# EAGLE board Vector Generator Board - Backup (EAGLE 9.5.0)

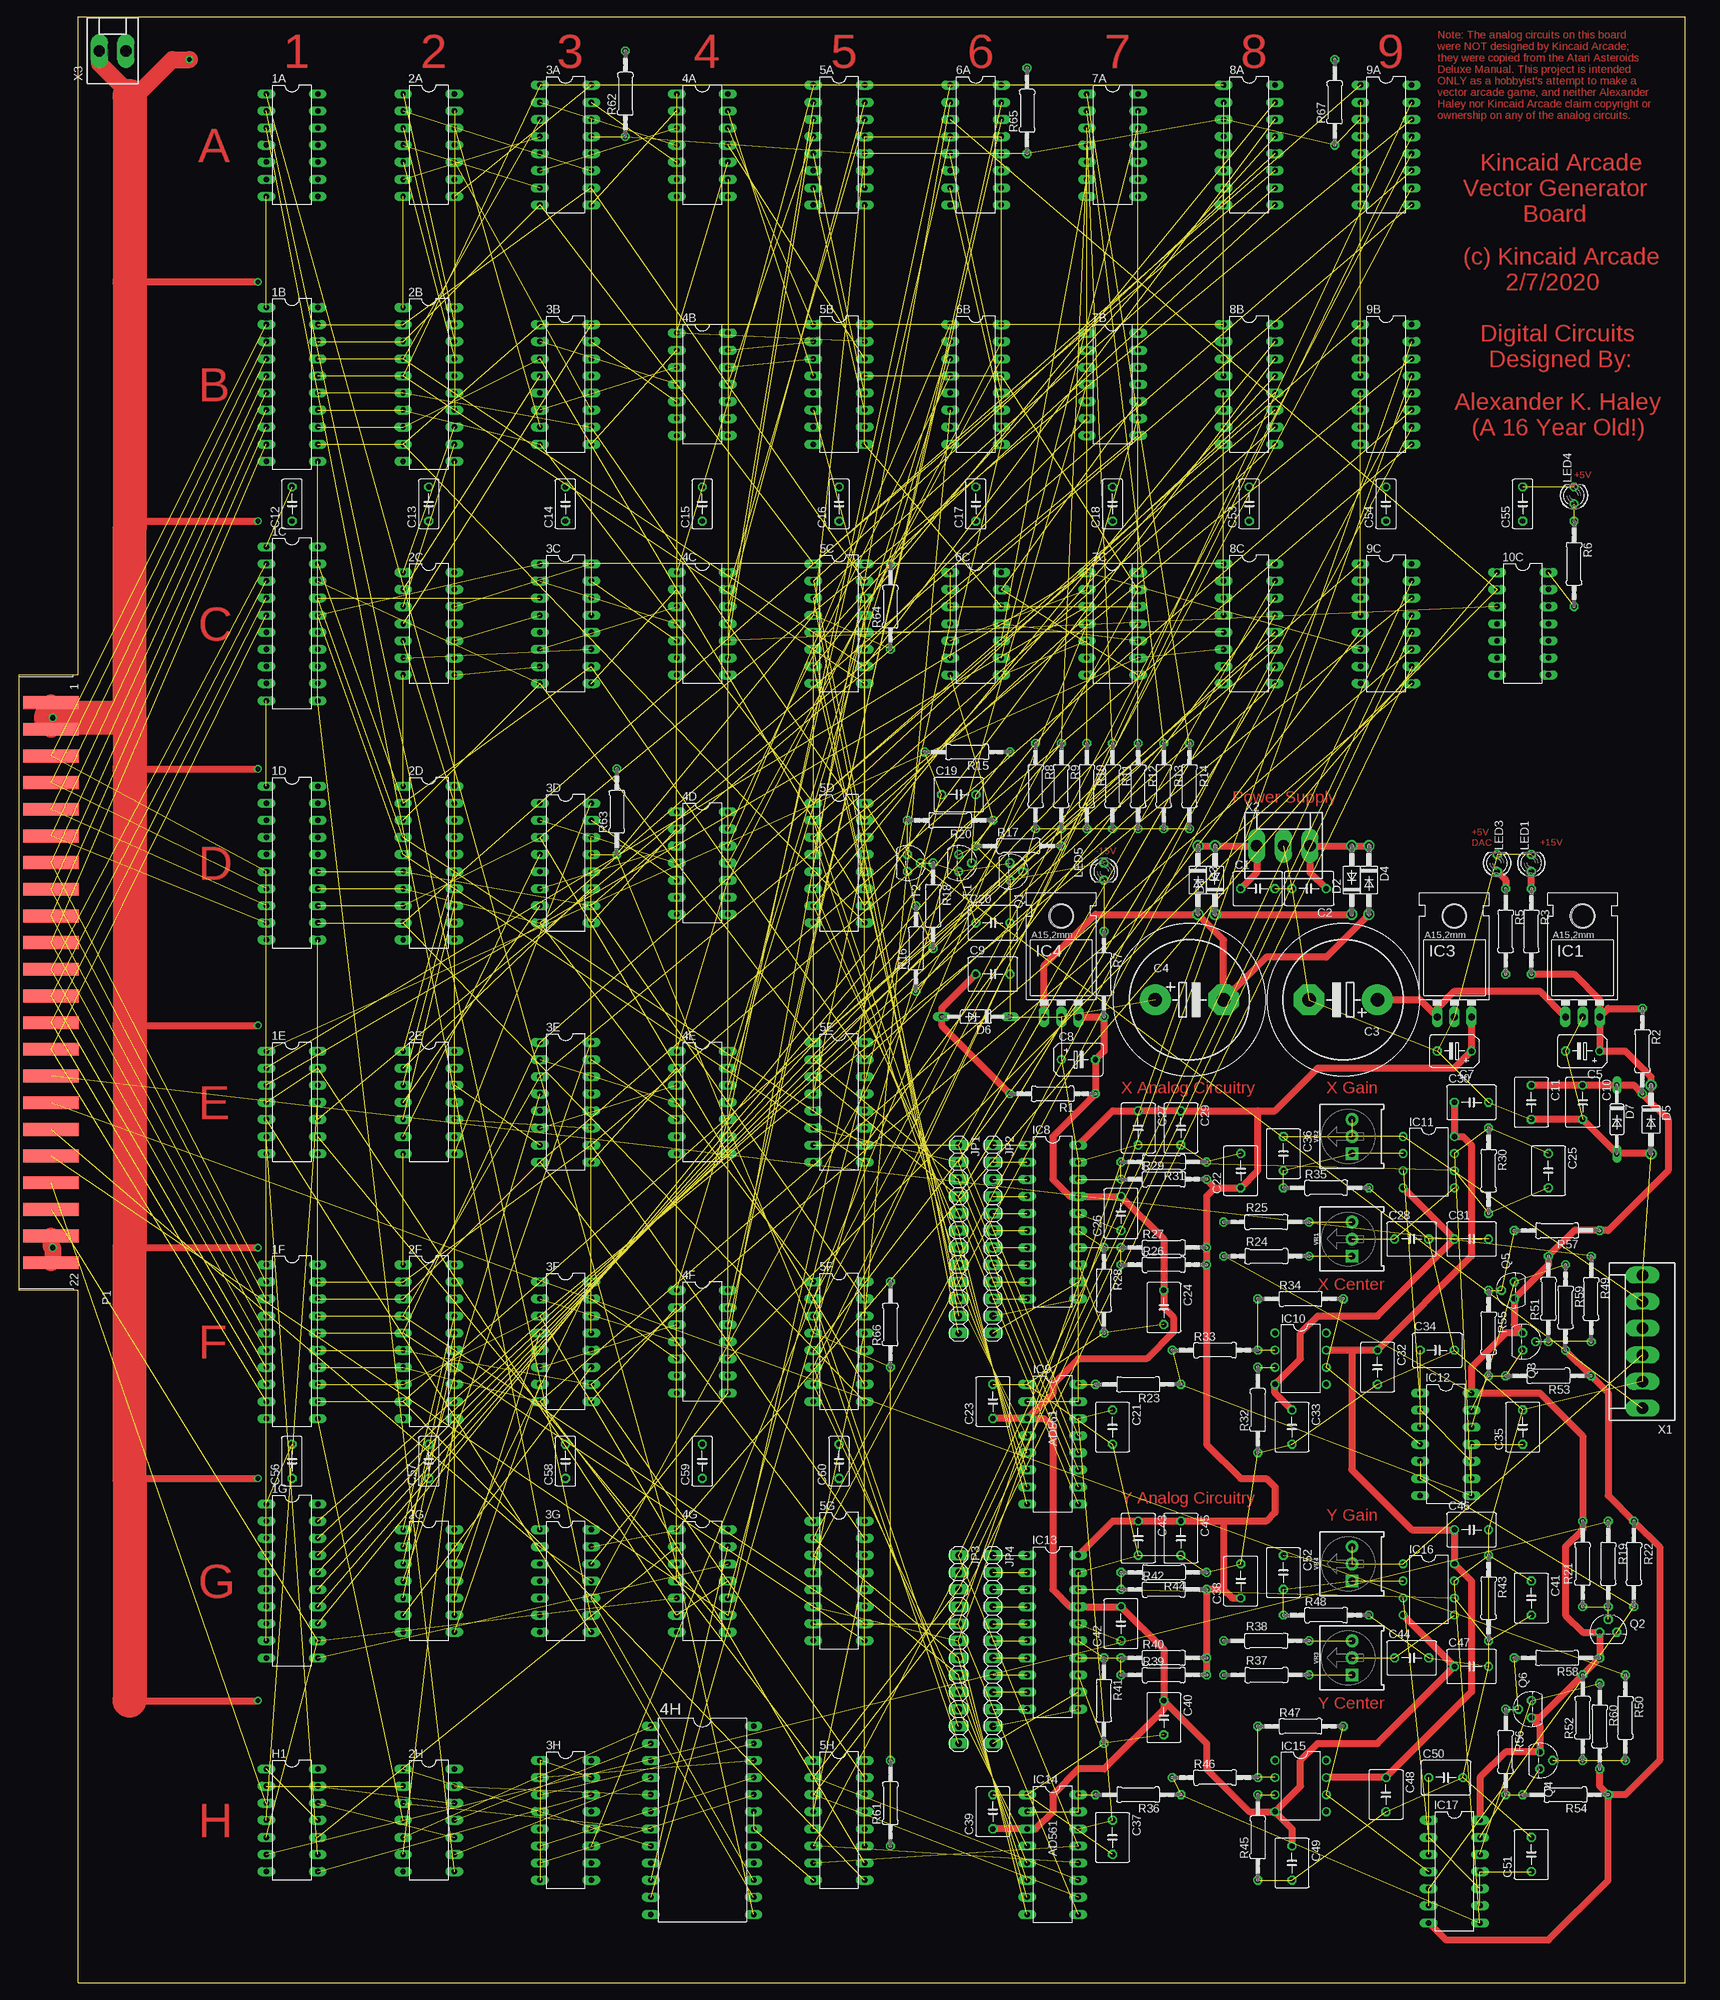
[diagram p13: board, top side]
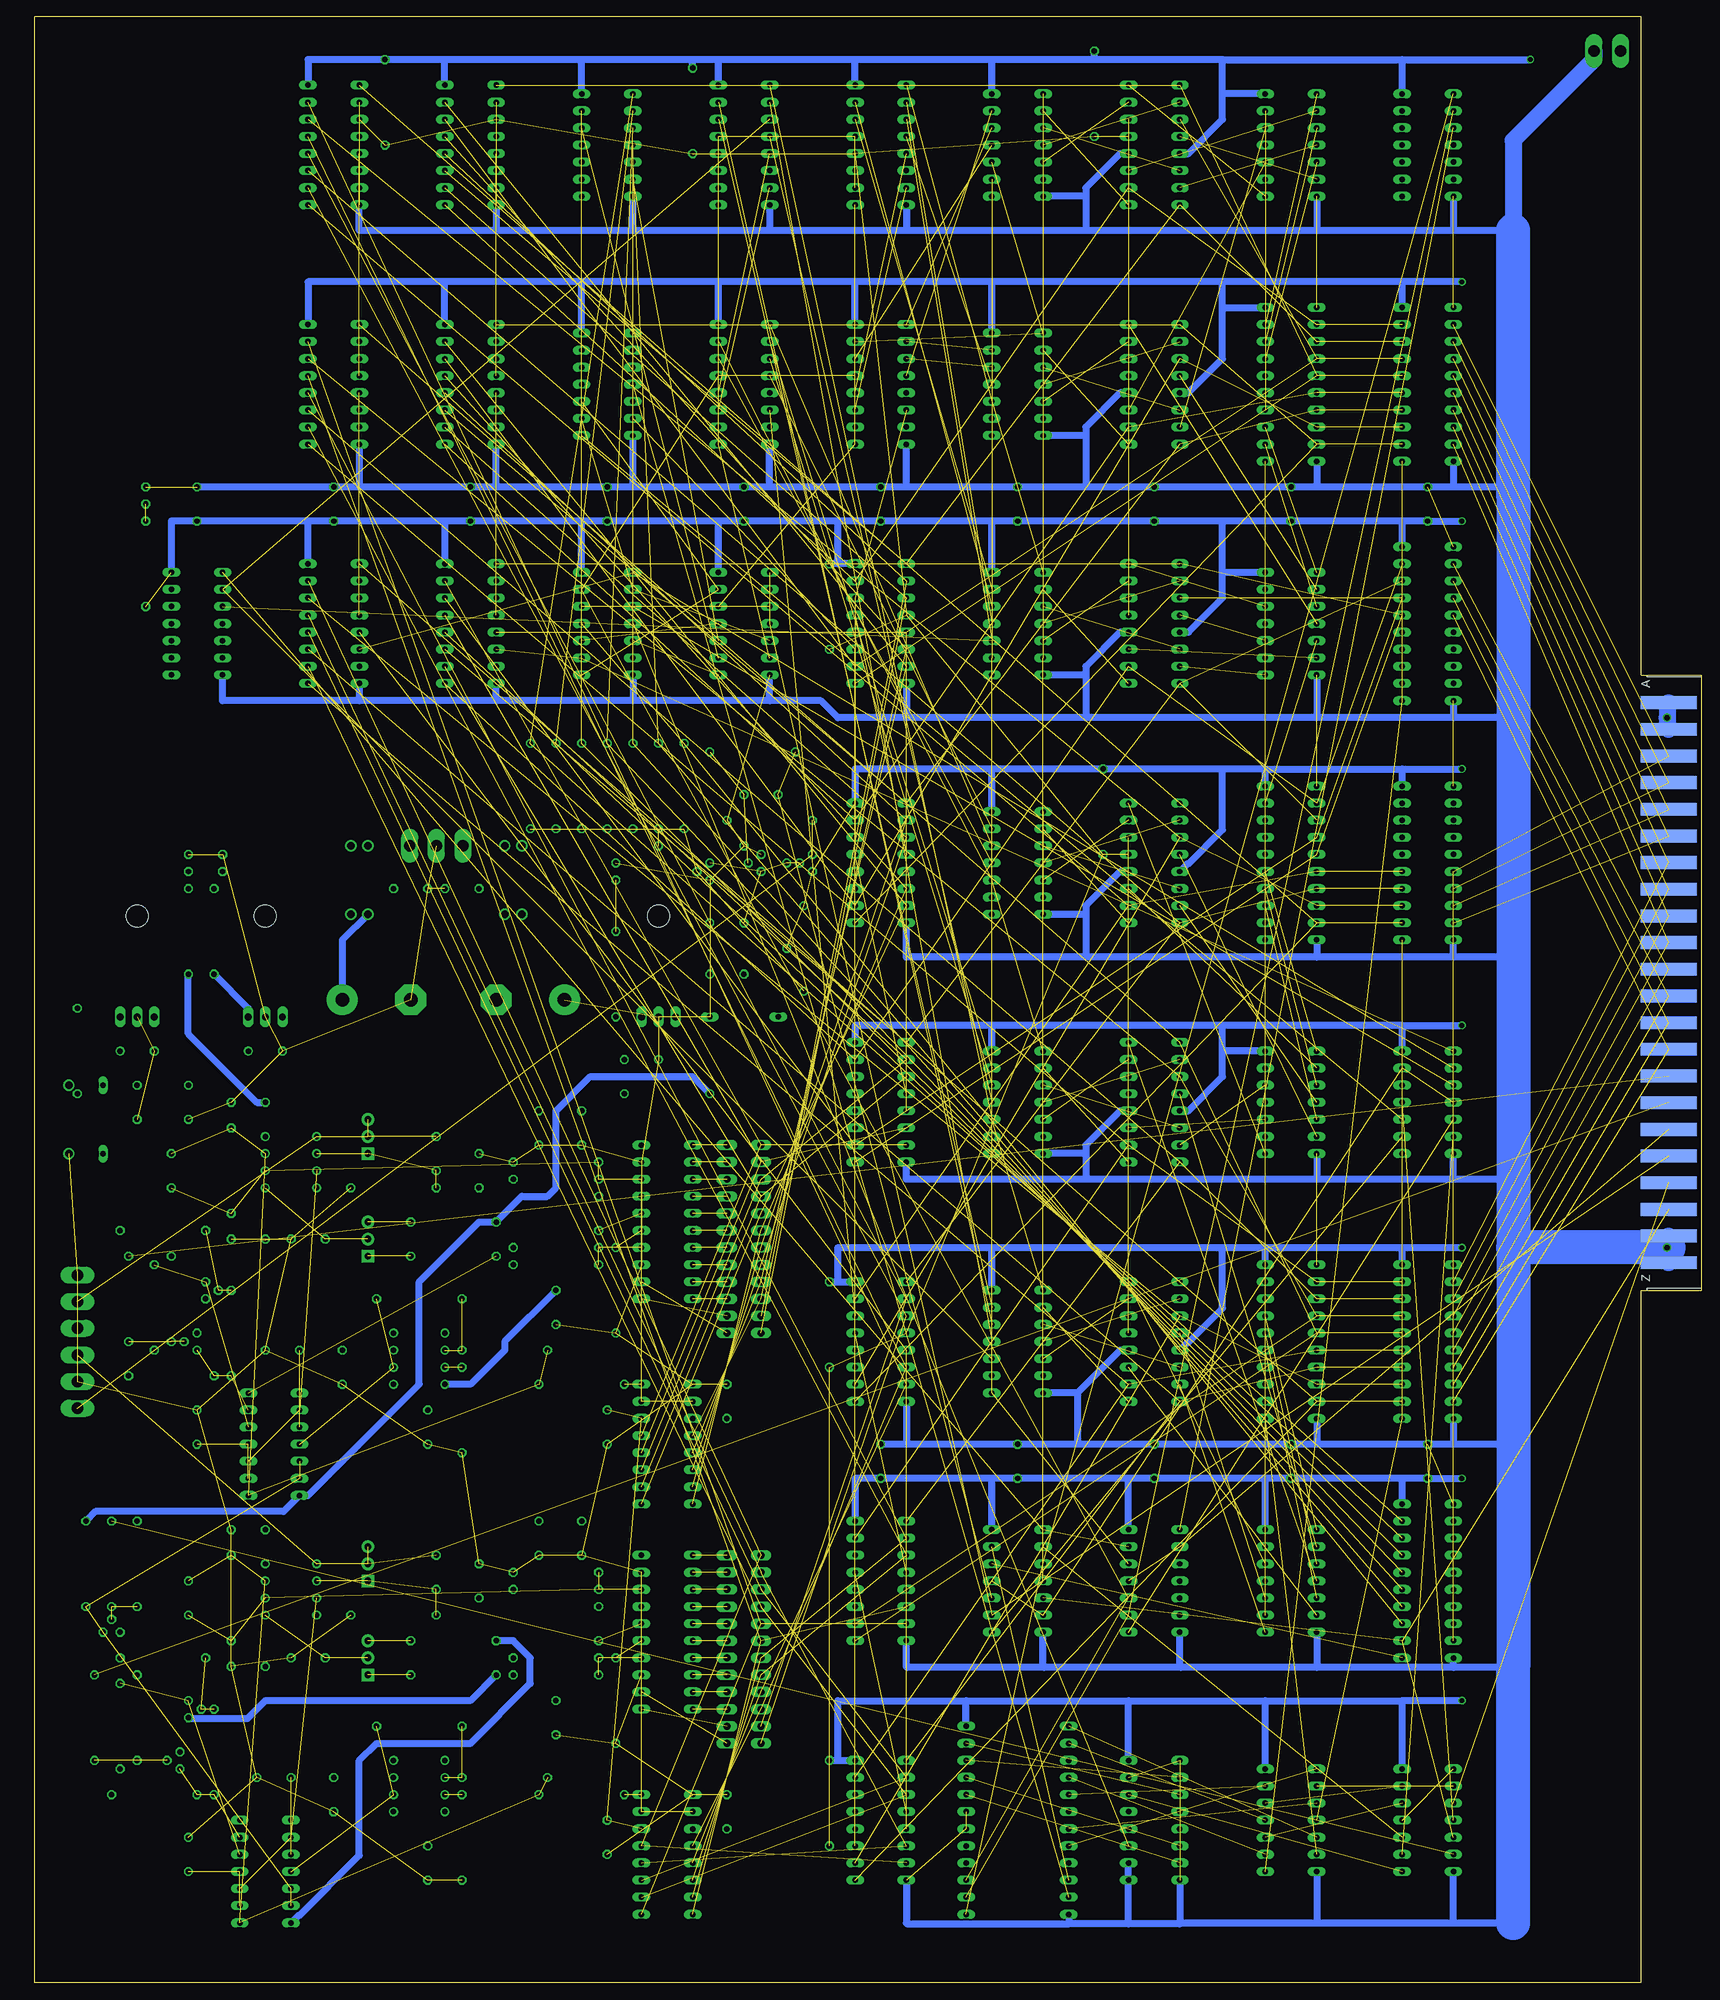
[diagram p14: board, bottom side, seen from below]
Size 247.65 x 292.1 mm. Coordinates in mm from the lower left corner, seen from the top.
Outline: 8.89,0 8.89,102.87 0,102.87 0,194.31 8.89,194.31 8.89,292.1 247.65,292.1 247.65,0 8.89,0
Copper layers (1*16): Top 0.035mm / dielectric 1.5mm / Bottom 0.035mm
Design rules "default": minimum track width 6mil, minimum drill 0.35mm, track to track 6mil, track to pad 6mil, pad to pad 6mil, via to via 6mil, smd to smd 6mil, copper to edge 40mil, drill to drill 6mil, minimum pad ring 10mil, minimum via ring 8mil, stop-mask expansion 4mil, vias tented up to drill 0mil, thermal gap 10mil
Net classes: 0 default: width 0.381 mm, clearance 0.203 mm

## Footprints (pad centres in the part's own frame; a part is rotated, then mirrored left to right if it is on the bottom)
DIL14 = drill 0.813 long: 1 -7.62,-3.81; 2 -5.08,-3.81; 3 -2.54,-3.81; 4 0,-3.81; 5 2.54,-3.81; 6 5.08,-3.81; 7 7.62,-3.81; 8 7.62,3.81; 9 5.08,3.81; 10 2.54,3.81; 11 0,3.81; 12 -2.54,3.81; 13 -5.08,3.81; 14 -7.62,3.81
DIL20 = drill 0.813 long: 1 -11.43,-3.81; 2 -8.89,-3.81; 3 -6.35,-3.81; 4 -3.81,-3.81; 5 -1.27,-3.81; 6 1.27,-3.81; 7 3.81,-3.81; 8 6.35,-3.81; 9 8.89,-3.81; 10 11.43,-3.81; 11 11.43,3.81; 12 8.89,3.81; 13 6.35,3.81; 14 3.81,3.81; 15 1.27,3.81; 16 -1.27,3.81; 17 -3.81,3.81; 18 -6.35,3.81; 19 -8.89,3.81; 20 -11.43,3.81
DIL16 = drill 0.813 long: 1 -8.89,-3.81; 2 -6.35,-3.81; 3 -3.81,-3.81; 4 -1.27,-3.81; 5 1.27,-3.81; 6 3.81,-3.81; 7 6.35,-3.81; 8 8.89,-3.81; 9 8.89,3.81; 10 6.35,3.81; 11 3.81,3.81; 12 1.27,3.81; 13 -1.27,3.81; 14 -3.81,3.81; 15 -6.35,3.81; 16 -8.89,3.81
DIL24-6 = drill 0.813 long: 1 -13.97,-7.62; 2 -11.43,-7.62; 3 -8.89,-7.62; 4 -6.35,-7.62; 5 -3.81,-7.62; 6 -1.27,-7.62; 7 1.27,-7.62; 8 3.81,-7.62; 9 6.35,-7.62; 10 8.89,-7.62; 11 11.43,-7.62; 12 13.97,-7.62; 13 13.97,7.62; 14 11.43,7.62; 15 8.89,7.62; 16 6.35,7.62; 17 3.81,7.62; 18 1.27,7.62; 19 -1.27,7.62; 20 -3.81,7.62; 21 -6.35,7.62; 22 -8.89,7.62; 23 -11.43,7.62; 24 -13.97,7.62
C050-050X075 = drill 0.813 octagon: 1 -2.54,0; 2 2.54,0
EB22,5D = drill 2.007 pad 4.597: + -5.08,0 | drill 2.007 pad 4.597 octagon: - 5.08,0
B45181B = drill 0.813: + -2.54,0 | drill 0.813 octagon: - 2.54,0
C050-030X075 = drill 0.813 octagon: 1 -2.54,0; 2 2.54,0
DO41-10 = drill 1.118: A 5.08,0; C -5.08,0
DO35Z10 = drill 0.813 long: A 5.08,0; C -5.08,0
78XXL = drill 1.016 long: GND 0,-3.81; IN -2.54,-3.81; OUT 2.54,-3.81 | hole 3.302: 0,11.176
DIL08 = drill 0.813 pad 1.27: 1 -3.81,-3.81; 2 -1.27,-3.81; 3 1.27,-3.81; 4 3.81,-3.81; 5 3.81,3.81; 6 1.27,3.81; 7 -1.27,3.81; 8 -3.81,3.81
1X12 = drill 1.016 long: 1 -13.97,0; 2 -11.43,0; 3 -8.89,0; 4 -6.35,0; 5 -3.81,0; 6 -1.27,0; 7 1.27,0; 8 3.81,0; 9 6.35,0; 10 8.89,0; 11 11.43,0; 12 13.97,0
LED3MM = drill 0.813 octagon: A -1.27,0; K 1.27,0
44PINEDGE = smd 1.905 x 8.255: 1 -41.605,4.826; 2 -37.643,4.826; 3 -33.68,4.826; 4 -29.718,4.826; 5 -25.756,4.826; 6 -21.793,4.826; 7 -17.831,4.826; 8 -13.868,4.826; 9 -9.906,4.826; 10 -5.944,4.826; 11 -1.981,4.826; 12 1.981,4.826; 13 5.944,4.826; 14 9.906,4.826; 15 13.868,4.826; 16 17.831,4.826; 17 21.793,4.826; 18 25.756,4.826; 19 29.718,4.826; 20 33.68,4.826; 21 37.643,4.826; 22 41.605,4.826 | smd 1.905 x 8.255 bottom: A -41.605,4.826; B -37.643,4.826; C -33.68,4.826; D -29.718,4.826; E -25.756,4.826; F -21.793,4.826; H -17.831,4.826; J -13.868,4.826; K -9.906,4.826; L -5.944,4.826; M -1.981,4.826; N 1.981,4.826; P 5.944,4.826; R 9.906,4.826; S 13.868,4.826; T 17.831,4.826; U 21.793,4.826; V 25.756,4.826; W 29.718,4.826; X 33.68,4.826; Y 37.643,4.826; Z 41.605,4.826
TO92 = drill 0.813 octagon: 1 1.27,0; 2 0,1.905; 3 -1.27,0
0207/12 = drill 0.813 octagon: 1 -6.35,0; 2 6.35,0
TRIMPOT-PTH-3386U = drill 1.016 pad 1.88 square: 1 -2.54,-0.015 | drill 1.016 pad 1.88: 2 0,-0.015; 3 2.54,-0.015
KK-156-6 = drill 1.7 pad 2.184 long: 1 -9.9,0; 2 -5.94,0; 3 -1.98,0; 4 1.98,0; 5 5.94,0; 6 9.9,0
KK-156-3 = drill 1.7 pad 2.184 long: 1 -3.96,0; 2 0,0; 3 3.96,0
KK-156-2 = drill 1.7 pad 2.184 long: 1 -1.98,0; 2 1.98,0

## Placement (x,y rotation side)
1A  7400N  [DIL14]  40.64,273.05 270 top
1B  74HC573N  [DIL20]  40.64,237.49 270 top
1C  74HC573N  [DIL20]  40.64,201.93 270 top
1D  74HC573N  [DIL20]  40.64,166.37 270 top
1E  74S08N  [DIL14]  40.64,130.81 270 top
1F  74HC573N  [DIL20]  40.64,95.25 270 top
1G  74HC573N  [DIL20]  40.64,59.69 270 top
2A  7404N  [DIL14]  60.96,273.05 270 top
2B  74HC573N  [DIL20]  60.96,237.49 270 top
2C  7404N  [DIL14]  60.96,201.93 270 top
2D  74HC573N  [DIL20]  60.96,166.37 270 top
2E  7404N  [DIL14]  60.96,130.81 270 top
2F  74HC573N  [DIL20]  60.96,95.25 270 top
2G  7404N  [DIL14]  60.96,59.69 270 top
2H  7404N  [DIL14]  60.96,24.13 270 top
3A  7483N  [DIL16]  81.28,273.05 270 top
3B  7483N  [DIL16]  81.28,237.49 270 top
3C  7483N  [DIL16]  81.28,201.93 270 top
3D  7483N  [DIL16]  81.28,166.37 270 top
3E  7483N  [DIL16]  81.28,130.81 270 top
3F  7483N  [DIL16]  81.28,95.25 270 top
3G  74S11N  [DIL14]  81.28,59.69 270 top
3H  74191N  [DIL16]  81.28,24.13 270 top
4A  7495N  [DIL14]  101.6,273.05 270 top
4B  7495N  [DIL14]  101.6,237.49 270 top
4C  7495N  [DIL14]  101.6,201.93 270 top
4D  7495N  [DIL14]  101.6,166.37 270 top
4E  7495N  [DIL14]  101.6,130.81 270 top
4F  7495N  [DIL14]  101.6,95.25 270 top
4G  7404N  [DIL14]  101.6,59.69 270 top
4H  74154N  [DIL24-6]  101.6,24.13 270 top
5A  7497N  [DIL16]  121.92,273.05 270 top
5B  7497N  [DIL16]  121.92,237.49 270 top
5C  74191N  [DIL16]  121.92,201.93 270 top
5D  74191N  [DIL16]  121.92,166.37 270 top
5E  74191N  [DIL16]  121.92,130.81 270 top
5F  74191N  [DIL16]  121.92,95.25 270 top
5G  74191N  [DIL16]  121.92,59.69 270 top
5H  74191N  [DIL16]  121.92,24.13 270 top
6A  7497N  [DIL16]  142.24,273.05 270 top
6B  7497N  [DIL16]  142.24,237.49 270 top
6C  74S11N  [DIL14]  142.24,201.93 270 top
7A  74LS27N  [DIL14]  162.56,273.05 270 top
7B  7432N  [DIL14]  162.56,237.49 270 top
7C  7404N  [DIL14]  162.56,201.93 270 top
8A  7485N  [DIL16]  182.88,273.05 270 top
8B  7485N  [DIL16]  182.88,237.49 270 top
8C  7485N  [DIL16]  182.88,201.93 270 top
9A  7485N  [DIL16]  203.2,273.05 270 top
9B  7485N  [DIL16]  203.2,237.49 270 top
9C  7485N  [DIL16]  203.2,201.93 270 top
10C  7402N  [DIL14]  223.52,201.93 270 top
C1  .1 uf  [C050-050X075]  184.15,162.56 0 top
C2  .1 uf  [C050-050X075]  191.77,162.56 180 top
C3  470 uf  [EB22,5D]  196.85,146.05 180 top
C4  470 uf  [EB22,5D]  173.99,146.05 0 top
C5  1 uf  [B45181B]  232.41,138.43 180 top
C7  1 uf  [B45181B]  213.36,138.43 180 top
C8  1 uf  [B45181B]  157.48,137.16 0 top
C9  .1 uf  [C050-050X075]  144.78,149.86 0 top
C10  .1 uf  [C050-050X075]  232.41,130.81 270 top
C11  22pf  [C050-050X075]  224.79,130.81 270 top
C12  .1uf  [C050-030X075]  40.64,219.71 90 top
C13  .1uf  [C050-030X075]  60.96,219.71 90 top
C14  .1uf  [C050-030X075]  81.28,219.71 90 top
C15  .1uf  [C050-030X075]  101.6,219.71 90 top
C16  .1uf  [C050-030X075]  121.92,219.71 90 top
C17  .1uf  [C050-030X075]  142.24,219.71 90 top
C18  .1uf  [C050-030X075]  162.56,219.71 90 top
C19  270pf  [C050-050X075]  139.7,176.53 0 top
C20  .01uf  [C050-050X075]  144.78,157.48 0 top
C21  .1uf  [C050-050X075]  162.56,82.55 270 top
C22  .1uf  [C050-050X075]  181.61,120.65 90 top
C23  .1uf  [C050-050X075]  144.78,86.36 90 top
C24  .1uf  [C050-050X075]  170.18,100.33 270 top
C25  10pf  [C050-050X075]  227.33,120.65 270 top
C26  .01uf  [C050-050X075]  163.83,114.3 90 top
C27  .1uf  [C050-050X075]  166.37,127 270 top
C28  .1uf  [C050-050X075]  207.01,110.49 0 top
C29  .1uf  [C050-050X075]  172.72,127 270 top
C30  .1uf  [C050-050X075]  215.9,130.81 0 top
C31  .1uf  [C050-050X075]  215.9,110.49 0 top
C32  .1uf  [C050-050X075]  201.93,91.44 270 top
C33  .1uf  [C050-050X075]  189.23,82.55 270 top
C34  220pf  [C050-050X075]  210.82,93.98 0 top
C35  220pf  [C050-050X075]  223.52,82.55 90 top
C36  69pf  [C050-050X075]  187.96,123.19 270 top
C37  .1uf  [C050-050X075]  162.56,21.59 270 top
C38  .1uf  [C050-050X075]  181.61,59.69 90 top
C39  .1uf  [C050-050X075]  144.78,25.4 90 top
C40  .1uf  [C050-050X075]  170.18,39.37 270 top
C41  10pf  [C050-050X075]  224.79,57.15 270 top
C42  .01uf  [C050-050X075]  163.83,53.34 90 top
C43  .1uf  [C050-050X075]  166.37,66.04 270 top
C44  .1uf  [C050-050X075]  207.01,48.26 0 top
C45  .1uf  [C050-050X075]  172.72,66.04 270 top
C46  .1uf  [C050-050X075]  215.9,67.31 0 top
C47  .1uf  [C050-050X075]  215.9,46.99 0 top
C48  .1uf  [C050-050X075]  203.2,27.94 270 top
C49  .1uf  [C050-050X075]  189.23,17.78 270 top
C50  220pf  [C050-050X075]  212.09,30.48 0 top
C51  220pf  [C050-050X075]  224.79,19.05 90 top
C52  69pf  [C050-050X075]  187.96,60.96 270 top
C53  .1uf  [C050-030X075]  182.88,219.71 90 top
C54  .1uf  [C050-030X075]  203.2,219.71 90 top
C55  .1uf  [C050-030X075]  223.52,219.71 90 top
C56  .1uf  [C050-030X075]  40.64,77.47 90 top
C57  .1uf  [C050-030X075]  60.96,77.47 90 top
C58  .1uf  [C050-030X075]  81.28,77.47 90 top
C59  .1uf  [C050-030X075]  101.6,77.47 90 top
C60  .1uf  [C050-030X075]  121.92,77.47 90 top
D1  1N4004  [DO41-10]  177.8,163.83 90 top
D2  1N4004  [DO41-10]  198.12,163.83 90 top
D3  1N4004  [DO41-10]  175.26,163.83 270 top
D4  1N4004  [DO41-10]  200.66,163.83 270 top
D5  NTE109  [DO41-10]  242.57,128.27 270 top
D6  NTE5016  [DO35Z10]  142.24,143.51 180 top
D7  1n756a  [DO35Z10]  237.49,128.27 270 top
H1  7432N  [DIL14]  40.64,24.13 270 top
IC1  7815  [78XXL]  232.41,147.32 0 top
IC3  7805  [78XXL]  213.36,147.32 0 top
IC4  7915  [78XXL]  154.94,147.32 0 top
IC8  DAC312  [DIL20]  153.67,113.03 270 top
IC9  AD561  [DIL16]  153.67,80.01 270 top
IC10  TL081P  [DIL08]  190.5,92.71 270 top
IC11  TL082P  [DIL08]  209.55,121.92 270 top
IC12  4016N  [DIL14]  212.09,80.01 270 top
IC13  DAC312  [DIL20]  153.67,52.07 270 top
IC14  AD561  [DIL16]  153.67,19.05 270 top
IC15  TL081P  [DIL08]  190.5,29.21 270 top
IC16  TL082P  [DIL08]  209.55,58.42 270 top
IC17  4016N  [DIL14]  213.36,16.51 270 top
JP1  [1X12]  139.7,110.49 270 top
JP2  [1X12]  144.78,110.49 270 top
JP3  [1X12]  139.7,49.53 270 top
JP4  [1X12]  144.78,49.53 270 top
LED1  [LED3MM]  224.79,166.37 90 top
LED3  [LED3MM]  219.71,166.37 90 top
LED4  [LED3MM]  231.14,220.98 90 top
LED5  [LED3MM]  161.29,165.1 270 top
P1  44PINEDGE  [44PINEDGE]  0,148.59 270 top
Q1  2N3906  [TO92]  147.32,165.1 270 top
Q2  2N3906  [TO92]  236.22,52.07 0 top
Q3  2N3906  [TO92]  223.52,95.25 270 top
Q4  2N3906  [TO92]  226.06,33.02 270 top
Q5  2N3906  [TO92]  222.25,102.87 90 top
Q6  2N3906  [TO92]  224.79,40.64 90 top
R1  270  [0207/12]  153.67,132.08 180 top
R2  270  [0207/12]  241.3,138.43 270 top
R3  680  [0207/12]  224.79,156.21 270 top
R5  150  [0207/12]  220.98,156.21 270 top
R6  150  [0207/12]  231.14,210.82 270 top
R7  680  [0207/12]  161.29,149.86 270 top
R8  1.2K  [0207/12]  151.13,177.8 270 top
R9  2.2K  [0207/12]  154.94,177.8 270 top
R10  4.7K  [0207/12]  158.75,177.8 270 top
R11  10K  [0207/12]  162.56,177.8 270 top
R12  22K  [0207/12]  166.37,177.8 270 top
R13  47K  [0207/12]  170.18,177.8 270 top
R14  82K  [0207/12]  173.99,177.8 270 top
R15  1K  [0207/12]  140.97,182.88 180 top
R16  12K  [0207/12]  133.35,153.67 90 top
R17  150K  [0207/12]  148.59,168.91 0 top
R18  68  [0207/12]  135.89,160.02 270 top
R19  18K  [0207/12]  236.22,62.23 270 top
R20  27  [0207/12]  138.43,172.72 180 top
R21  2.2K  [0207/12]  232.41,62.23 90 top
R22  3.3K  [0207/12]  240.03,62.23 270 top
R23  2.2K  [0207/12]  166.37,88.9 180 top
R24  56K  [0207/12]  185.42,107.95 180 top
R25  56K  [0207/12]  185.42,113.03 0 top
R26  10k  [0207/12]  170.18,106.68 0 top
R27  10k  [0207/12]  170.18,109.22 0 top
R28  4.7K  [0207/12]  161.29,102.87 270 top
R29  10K  [0207/12]  170.18,119.38 0 top
R30  8.2K  [0207/12]  218.44,120.65 270 top
R31  2.2K  [0207/12]  170.18,121.92 180 top
R32  4.7K  [0207/12]  184.15,85.09 90 top
R33  10K  [0207/12]  177.8,93.98 0 top
R34  10K  [0207/12]  190.5,101.6 0 top
R35  3.9K  [0207/12]  194.31,118.11 0 top
R36  2.2K  [0207/12]  166.37,27.94 180 top
R37  56K  [0207/12]  185.42,45.72 180 top
R38  56K  [0207/12]  185.42,50.8 0 top
R39  10k  [0207/12]  170.18,45.72 0 top
R40  10k  [0207/12]  170.18,48.26 0 top
R41  4.7K  [0207/12]  161.29,41.91 270 top
R42  10K  [0207/12]  170.18,58.42 0 top
R43  8.2K  [0207/12]  218.44,57.15 270 top
R44  2.2K  [0207/12]  170.18,60.96 180 top
R45  4.7K  [0207/12]  184.15,21.59 90 top
R46  10K  [0207/12]  177.8,30.48 0 top
R47  10K  [0207/12]  190.5,38.1 0 top
R48  3.9K  [0207/12]  194.31,54.61 0 top
R49  18K  [0207/12]  233.68,101.6 270 top
R50  18K  [0207/12]  238.76,39.37 270 top
R51  2.2K  [0207/12]  227.33,101.6 90 top
R52  2.2K  [0207/12]  232.41,39.37 90 top
R53  3.3K  [0207/12]  227.33,90.17 180 top
R54  3.3K  [0207/12]  229.87,27.94 180 top
R55  100K  [0207/12]  218.44,96.52 270 top
R56  100K  [0207/12]  220.98,34.29 270 top
R57  4.7K  [0207/12]  228.6,111.76 180 top
R58  4.7K  [0207/12]  228.6,48.26 180 top
R59  56K  [0207/12]  229.87,100.33 270 top
R60  56K  [0207/12]  234.95,38.1 270 top
R61  1K  [0207/12]  129.54,26.67 90 top
R62  1K  [0207/12]  90.17,280.67 90 top
R63  1K  [0207/12]  88.9,173.99 90 top
R64  1K  [0207/12]  129.54,204.47 90 top
R65  1K  [0207/12]  149.86,278.13 90 top
R66  1K  [0207/12]  129.54,97.79 90 top
R67  1K  [0207/12]  195.58,279.4 90 top
T1  2N3904  [TO92]  139.7,166.37 270 top
T2  2N3904  [TO92]  132.08,166.37 270 top
VR1  10k  [TRIMPOT-PTH-3386U]  198.12,110.49 90 top
VR2  10k  [TRIMPOT-PTH-3386U]  198.12,125.73 90 top
VR3  10k  [TRIMPOT-PTH-3386U]  198.12,48.26 90 top
VR4  10k  [TRIMPOT-PTH-3386U]  198.12,62.23 90 top
X1  [KK-156-6]  241.3,95.25 90 top
X2  [KK-156-3]  187.96,168.91 0 top
X3  [KK-156-2]  13.97,287.02 0 top

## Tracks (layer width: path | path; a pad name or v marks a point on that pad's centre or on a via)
2.5MHZ  (4 unrouted)
20MHZ  (3 unrouted)
25VAC_A
  Top 1.016: D3.C D1.A X2.1 184,164.95 C1.1
25VAC_B
  Top 1.016: C2.1 191.92,164.95 X2.3 D2.A D4.C
+5V_DAC
  Top 1.016: IC3.OUT C7.+ 213.36,135.89 193.04,135.89 186.69,129.54 184.15,129.54 | 184.15,129.54 184.15,120.65 C22.1 177.8,118.11 | 184.15,129.54 C29.1 C27.1 162.56,129.54 IC8.20 | R29.2 177.8,118.11 | 177.8,118.11 176.53,116.84 R27.2 R26.2 176.53,80.01 181.61,74.93 185.42,74.93 186.69,73.66 186.69,69.85 185.42,68.58 179.07,68.58 | 179.07,68.58 C45.1 C43.1 162.56,68.58 IC13.20 | 179.07,68.58 179.07,58.42 | 179.07,58.42 R42.2 R40.2 R39.2 | 179.07,58.42 180.34,57.15 C38.1
  Bottom 1.016: IC3.OUT 215.9,144.78 R5.2
+5VDC  (3 unrouted)
+8.2VDC  (1 unrouted)
  Top 1.016: C11.1 C10.1 D7.C 240.03,133.35 R2.2 245.11,128.27 245.11,120.65 236.22,111.76 R57.1 231.14,111.76 R51.2 227.33,106.68 Q5.3 222.25,97.79 Q3.3 220.98,96.52 215.9,91.44 IC12.14 226.06,87.63 232.41,81.28 R21.2 232.41,67.31 229.87,64.77 229.87,54.61 232.41,52.07 Q2.3 R58.1 R52.2 226.06,39.37 Q6.3 226.06,38.1 Q4.3 220.98,34.29 217.17,30.48 IC17.14
  Bottom 1.016: R37.2 182.88,41.91 213.36,41.91 216.05,39.22 224.64,39.22 Q6.3
+15VDC
  Top 1.016: IC1.OUT C5.+ 238.76,138.43 242.57,134.62 D5.C | IC1.OUT 236.22,144.78 R2.1 | R3.2 231.14,149.86 234.95,146.05 IC1.OUT | C30.1 IC11.8 214.63,125.73 215.9,124.46 215.9,107.95 C32.1 198.12,93.98 | 198.12,93.98 IC10.7 | 198.12,93.98 198.12,76.2 207.01,67.31 C46.1 IC16.8 215.9,59.69 215.9,43.18 C48.1 IC15.7
  Bottom 1.016: C30.1 214.63,130.81 224.79,140.97 R3.2
+22VDC
  Top 1.016: C3.+ 208.28,146.05 IC3.IN 210.82,144.78 213.36,147.32 226.06,147.32 IC1.IN | D1.C D2.C
  Bottom 1.016: D2.C 201.93,154.94 C3.+
-8.2VDC
  Top 1.016: R1.2 137.16,142.24 D6.A 137.16,144.78 C9.1 | R59.2 R53.1 236.22,87.63 236.22,72.39 R22.1 243.84,64.77 243.84,33.02 238.76,27.94 R54.1 | R54.1 234.95,29.21 R60.2 | IC17.7 212.09,6.35 227.33,6.35 236.22,15.24 R54.1
  Bottom 1.016: IC17.7 208.43,10.01 208.3,10.01 199.39,18.92 199.39,33.02 196.85,35.56 182.88,35.56 173.99,44.45 173.99,48.26 176.53,50.8 R38.1 | R22.1 238.61,70 210.67,70 IC12.7 207.01,72.39 190.5,88.9 190.5,104.14 181.61,113.03 R25.1 175.26,116.84 171.45,116.84 170.18,118.11 170.18,129.54 165.1,134.62 149.86,134.62 R1.2
-15VDC
  Top 1.016: IC4.OUT R7.2 161.29,138.43 C8.- R1.1 153.67,125.73 153.67,119.38 156.21,116.84 IC8.17 C26.2 170.18,110.49 C24.1 170.18,100.33 171.6,98.91 171.6,96.67 167.64,92.71 157.48,92.71 153.67,88.9 153.67,87.5 151.11,84.94 150.98,84.94 IC9.3 | IC9.3 C23.1 | IC9.3 152.4,83.82 153.67,82.55 153.67,58.42 156.21,55.88 IC13.17 C42.2 170.18,49.53 C40.1 | C40.1 170.18,40.64 161.29,31.75 157.48,31.75 153.67,27.94 153.67,25.4 151.13,22.86 IC14.3 C39.1 | C40.1 176.53,35.56 176.53,31.75 182.88,25.4 IC15.4 | IC15.4 189.23,22.86 C49.1 | IC15.4 190.5,29.21 190.5,33.02 193.04,35.56 201.93,35.56 C47.1 IC16.4 | C33.1 186.69,87.63 IC10.4 190.5,92.71 190.5,96.52 193.04,99.06 201.93,99.06 C31.1 IC11.4
  Bottom 1.016: C24.1 177.8,95.25 177.8,93.98 182.88,88.9 IC10.4
/BEAMOFF  (1 unrouted)
/COUNT  (10 unrouted)
/FRAMECOMPLETE  (3 unrouted)
/HALTROTATE  (2 unrouted)
/INHIBITX  (2 unrouted)
/INHIBITY  (2 unrouted)
/LDCOUNTERS  (6 unrouted)
/LDROT  (2 unrouted)
/LDX2  (1 unrouted)
/LDXY1  (1 unrouted)
/LDY2  (1 unrouted)
/LDZ  (1 unrouted)
/ROTATE  (2 unrouted)
/SUBTRACT  (1 unrouted)
/TTLINVX  (2 unrouted)
/TTLINVY  (2 unrouted)
/VECTORCOMPLETE  (1 unrouted)
/VRAMPC1  (1 unrouted)
/VRAMPC2  (1 unrouted)
/VRAMPC3  (1 unrouted)
/XCUR1  (1 unrouted)
/XCUR2  (1 unrouted)
/XCUR3  (1 unrouted)
/XCUR4  (1 unrouted)
/XCUR5  (1 unrouted)
/XCUR6  (1 unrouted)
/XCUR7  (1 unrouted)
/XCUR8  (1 unrouted)
/XCUR9  (1 unrouted)
/XCUR10  (1 unrouted)
/XCUR11  (1 unrouted)
/XCUR12  (1 unrouted)
/YCUR1  (1 unrouted)
/YCUR2  (1 unrouted)
/YCUR3  (1 unrouted)
/YCUR4  (1 unrouted)
/YCUR5  (1 unrouted)
/YCUR6  (1 unrouted)
/YCUR7  (1 unrouted)
/YCUR8  (1 unrouted)
/YCUR9  (1 unrouted)
/YCUR10  (1 unrouted)
/YCUR11  (1 unrouted)
/YCUR12  (1 unrouted)
A  (7 unrouted)
B  (7 unrouted)
BRMSACTIVE  (1 unrouted)
COUNT  (2 unrouted)
DACX1  (2 unrouted)
DACX2  (2 unrouted)
DACX3  (3 unrouted)
DACX4  (3 unrouted)
DACX5  (3 unrouted)
DACX6  (3 unrouted)
DACX7  (3 unrouted)
DACX8  (3 unrouted)
DACX9  (3 unrouted)
DACX10  (3 unrouted)
DACX11  (3 unrouted)
DACX12  (3 unrouted)
DACY1  (2 unrouted)
DACY2  (2 unrouted)
DACY3  (3 unrouted)
DACY4  (3 unrouted)
DACY5  (3 unrouted)
DACY6  (3 unrouted)
DACY7  (3 unrouted)
DACY8  (3 unrouted)
DACY9  (3 unrouted)
DACY10  (3 unrouted)
DACY11  (3 unrouted)
DACY12  (3 unrouted)
DX1  (1 unrouted)
DX2  (1 unrouted)
DX3  (1 unrouted)
DX4  (1 unrouted)
DX5  (1 unrouted)
DX6  (1 unrouted)
DX7  (1 unrouted)
DX8  (1 unrouted)
DX9  (1 unrouted)
DX10  (1 unrouted)
DX11  (1 unrouted)
DX12  (1 unrouted)
DY1  (1 unrouted)
DY2  (1 unrouted)
DY3  (1 unrouted)
DY4  (1 unrouted)
DY5  (1 unrouted)
DY6  (1 unrouted)
DY7  (1 unrouted)
DY8  (1 unrouted)
DY9  (1 unrouted)
DY10  (1 unrouted)
DY11  (1 unrouted)
DY12  (1 unrouted)
FRAMECOMPLETE  (4 unrouted)
GND  (via drill 0.8)  (86 unrouted)
  Top 1.016: D5.A D7.A C10.2 C11.2
  Top 2.54: P1.21 4.83,109.47 v5.08,109.22 5.08,107.24 P1.22
  Bottom 1.016: 3H.8 77.47,8.89 | 77.47,8.89 77.47,8.74 85.09,8.74 | 85.09,8.74 93.98,8.74 | 85.09,8.74 3H.9 3H.10 | 5H.8 118.11,8.89 117.96,8.74 93.98,8.74 | 4H.12 93.98,8.74 | 27.94,46.84 36.83,46.84 | 36.83,46.84 1G.10 | 36.83,46.84 57.15,46.84 | 57.15,46.84 77.32,46.84 | 3G.7 77.47,46.99 77.32,46.84 | 77.32,46.84 97.64,46.84 | 4G.7 97.79,46.99 97.64,46.84 | 97.64,46.84 117.96,46.84 118.11,46.99 5G.8 | 27.94,80.01 36.83,80.01 | 36.83,80.01 C56.2 57.15,80.01 | 57.15,80.01 C57.2 C58.2 92.71,80.01 | 92.71,80.01 C59.2 118.11,80.01 | 118.11,80.01 C60.2 | 2F.10 57.15,80.01 | 3F.12 86.36,93.98 92.71,87.63 | 92.71,87.63 92.71,80.01 | 92.71,87.63 4F.7 | 5F.8 118.11,80.01 | 27.94,119.38 36.83,119.38 | 36.83,119.38 57.15,119.38 | 36.83,119.38 1E.7 | 2E.7 57.15,119.38 | 57.15,119.38 91.44,119.38 | 3E.12 86.36,129.54 91.44,124.46 91.44,123.19 | 91.44,123.19 91.44,119.38 | 91.44,123.19 4E.7 | 91.44,119.38 118.11,119.38 5E.8 | 77.47,8.89 57.15,8.89 | 57.15,8.89 36.83,8.89 | 36.83,8.89 27.94,8.89 | 36.83,8.89 H1.7 | 2H.7 57.15,8.89 | 27.94,152.4 36.83,152.4 | 36.83,152.4 57.15,152.4 | 57.15,152.4 91.44,152.4 | 91.44,152.4 118.11,152.4 5D.8 | 3D.12 86.36,165.1 91.44,160.02 91.44,158.75 | 91.44,158.75 91.44,152.4 | 91.44,158.75 4D.7 | 2D.10 57.15,152.4 | 27.94,187.96 36.83,187.96 | 36.83,187.96 57.15,187.96 | 57.15,187.96 91.44,187.96 | 91.44,187.96 118.11,187.96 | 118.11,187.96 128.27,187.96 130.81,190.5 138.43,190.5 | 138.43,190.5 158.75,190.5 | 158.75,190.5 179.07,190.5 | 179.07,190.5 199.39,190.5 | 199.39,190.5 219.71,190.5 10C.7 | 9C.8 199.39,190.5 | 179.07,190.5 8C.8 | 7C.7 158.75,190.5 | 138.43,190.5 6C.7 | 5C.8 118.11,187.96 | 3C.12 86.36,200.66 91.44,195.58 91.44,194.31 | 91.44,194.31 91.44,187.96
  Bottom 1.016: 91.44,194.31 4C.7 | 2C.7 57.15,187.96 | 1C.10 36.83,187.96 | 27.94,220.98 29.21,222.25 36.83,222.25 | 36.83,222.25 C12.2 57.15,222.25 | 57.15,222.25 C13.2 C14.2 91.44,222.25 | 91.44,222.25 C15.2 118.11,222.25 | 118.11,222.25 C16.2 138.43,222.25 | 138.43,222.25 C17.2 158.75,222.25 | 158.75,222.25 C18.2 179.07,222.25 | 179.07,222.25 C53.2 199.39,222.25 | 199.39,222.25 C54.2 C55.2 | 9B.8 199.39,222.25 | 179.07,222.25 8B.8 | 158.75,222.25 7B.7 | 138.43,222.25 6B.8 | 118.11,222.25 5B.8 | 3B.12 86.36,236.22 91.44,231.14 91.44,229.87 | 91.44,229.87 91.44,222.25 | 91.44,229.87 4B.7 | 2B.10 57.15,222.25 | 1B.10 36.83,222.25 | 27.94,260.35 36.83,260.35 | 36.83,260.35 57.15,260.35 | 57.15,260.35 91.44,260.35 | 91.44,260.35 118.11,260.35 | 118.11,260.35 138.43,260.35 | 138.43,260.35 158.75,260.35 | 158.75,260.35 179.07,260.35 | 179.07,260.35 199.39,260.35 9A.8 | 8A.8 179.07,260.35 | 158.75,260.35 7A.7 | 6A.8 138.43,260.35 | 5A.8 118.11,260.35 | 3A.12 86.36,271.78 91.44,266.7 91.44,265.43 | 91.44,265.43 91.44,260.35 | 91.44,265.43 4A.7 | 2A.7 57.15,260.35 | 1A.7 36.83,260.35 | 2G.7 57.15,46.84 | 36.83,152.4 1D.10 | 1F.10 36.83,80.01
  Bottom 2.54: P1.21 4.83,109.22 P1.22 | X3.2 15.95,285.75 27.94,273.76 27.94,260.35
  Bottom 5.08: 4.83,109.22 v5.08,109.22 27.94,109.22 | 27.94,260.35 27.94,220.98 27.94,187.96 27.94,152.4 27.94,119.38 27.94,109.22 | 27.94,109.22 27.94,80.01 27.94,46.84 27.94,8.89
HALTROTATE  (1 unrouted)
INHIBITX  (2 unrouted)
INHIBITY  (2 unrouted)
INTENSITY0  (2 unrouted)
INTENSITY1  (2 unrouted)
INTENSITY2  (2 unrouted)
INTENSITY3  (2 unrouted)
INTENSITY4  (2 unrouted)
INTENSITY5  (2 unrouted)
INTENSITY6  (2 unrouted)
INVX  (3 unrouted)
INVY  (3 unrouted)
LDX2  (2 unrouted)
LDXY1  (3 unrouted)
LDY2  (2 unrouted)
LDZ  (1 unrouted)
N$1
  Top 1.016: IC4.IN 152.4,151.13 160.02,158.75 D3.A 179.07,154.94 C4.- 185.42,152.4 194.31,152.4 D4.A
N$2  (1 unrouted)
N$3  (1 unrouted)
N$4  (9 unrouted)
N$5  (2 unrouted)
N$6
  Top 1.016: R3.1 LED1.A
N$8
  Top 1.016: LED3.A 220.98,163.83 R5.1
N$9  (1 unrouted)
N$10  (1 unrouted)
N$11  (5 unrouted)
N$12  (4 unrouted)
N$13  (1 unrouted)
N$14  (2 unrouted)
N$15  (2 unrouted)
N$16  (2 unrouted)
N$17  (2 unrouted)
N$18  (2 unrouted)
N$19  (2 unrouted)
N$20  (1 unrouted)
N$21  (2 unrouted)
N$22  (1 unrouted)
N$23  (3 unrouted)
N$24  (1 unrouted)
N$25  (5 unrouted)
N$26  (1 unrouted)
N$27  (2 unrouted)
N$28  (2 unrouted)
N$29  (2 unrouted)
N$30  (2 unrouted)
N$31  (1 unrouted)
N$32  (2 unrouted)
N$33  (3 unrouted)
N$35  (2 unrouted)
N$36  (2 unrouted)
N$37  (2 unrouted)
N$38  (2 unrouted)
N$39  (2 unrouted)
N$40  (1 unrouted)
N$41  (1 unrouted)
N$42  (1 unrouted)
N$43  (1 unrouted)
N$44  (1 unrouted)
N$45  (1 unrouted)
N$46  (1 unrouted)
N$48  (1 unrouted)
N$49  (1 unrouted)
N$50  (1 unrouted)
N$51  (1 unrouted)
N$52  (1 unrouted)
N$53  (1 unrouted)
N$54  (1 unrouted)
N$55  (1 unrouted)
N$56  (1 unrouted)
N$57  (1 unrouted)
N$58  (1 unrouted)
N$59  (1 unrouted)
N$60  (1 unrouted)
N$61  (1 unrouted)
N$62  (1 unrouted)
N$63  (1 unrouted)
N$64  (1 unrouted)
N$65  (1 unrouted)
N$66  (1 unrouted)
N$67  (1 unrouted)
N$68  (1 unrouted)
N$69  (1 unrouted)
N$70  (1 unrouted)
N$71  (1 unrouted)
N$72  (1 unrouted)
N$73  (1 unrouted)
N$74  (1 unrouted)
N$75  (1 unrouted)
N$76  (1 unrouted)
N$77  (1 unrouted)
N$78  (1 unrouted)
N$79  (1 unrouted)
N$80  (1 unrouted)
N$81  (1 unrouted)
N$82  (1 unrouted)
N$83  (1 unrouted)
N$84  (1 unrouted)
N$85  (1 unrouted)
N$86  (1 unrouted)
N$87  (1 unrouted)
N$88  (1 unrouted)
N$89  (1 unrouted)
N$90  (1 unrouted)
N$91  (1 unrouted)
N$92  (1 unrouted)
N$93  (1 unrouted)
N$94  (1 unrouted)
N$95  (1 unrouted)
N$96  (1 unrouted)
N$97  (1 unrouted)
N$98  (1 unrouted)
N$100  (1 unrouted)
N$101  (1 unrouted)
N$102  (1 unrouted)
N$105  (1 unrouted)
N$106  (1 unrouted)
N$107  (1 unrouted)
N$108  (1 unrouted)
N$109  (1 unrouted)
N$110  (1 unrouted)
N$111  (1 unrouted)
N$112  (1 unrouted)
N$113  (1 unrouted)
N$114  (1 unrouted)
N$115  (2 unrouted)
N$116  (1 unrouted)
N$118  (1 unrouted)
N$119  (1 unrouted)
N$120  (1 unrouted)
N$121  (2 unrouted)
N$122  (1 unrouted)
N$123  (1 unrouted)
N$124  (2 unrouted)
N$125  (1 unrouted)
N$126  (1 unrouted)
N$127  (2 unrouted)
N$128  (1 unrouted)
N$129  (1 unrouted)
N$130  (1 unrouted)
N$131  (1 unrouted)
N$132  (1 unrouted)
N$133  (1 unrouted)
N$134  (1 unrouted)
N$135  (1 unrouted)
N$136  (1 unrouted)
N$138  (1 unrouted)
N$139  (1 unrouted)
N$140  (1 unrouted)
N$141  (1 unrouted)
N$155  (1 unrouted)
N$168  (2 unrouted)
N$169  (1 unrouted)
NINVX  (2 unrouted)
NINVY  (2 unrouted)
P  (14 unrouted)
ROTCLK  (12 unrouted)
ROTMODE  (6 unrouted)
SHCON  (5 unrouted)
U/DX  (3 unrouted)
U/DY  (3 unrouted)
VCC  (via drill 0.7, 0.8)  (4 unrouted)
  Top 1.016: 16.51,215.9 17.78,217.17 v35.56,217.17 | 16.51,142.24 v35.56,142.24 | 16.51,109.22 v35.56,109.22 | 16.51,74.93 v35.56,74.93 | 16.51,41.91 v35.56,41.91 | 16.51,180.34 v35.56,180.34 | 16.51,252.73 v35.56,252.73
  Top 2.54: P1.1 4.83,187.96 P1.2 | X3.1 11.99,285.19 16.88,280.3 | 16.51,280.3 16.88,280.3 | 16.88,280.3 17.41,280.3 22.86,285.75 v25.4,285.75
  Top 5.08: 16.51,280.3 16.51,252.73 16.51,215.9 16.51,187.96 | 4.83,187.96 v5.08,187.96 16.51,187.96 | 16.51,187.96 16.51,180.34 16.51,142.24 16.51,109.22 16.51,74.93 16.51,41.91
  Bottom 1.016: 9A.16 207.01,285.75 R67.2 186.69,285.75 | 71.12,285.75 44.45,285.75 | 71.12,285.75 90.17,285.75 | 90.17,285.75 105.41,285.75 | 105.41,285.75 125.73,285.75 | 125.73,285.75 146.05,285.75 | 146.05,285.75 149.86,285.75 | 149.86,285.75 166.37,285.75 | 166.37,285.75 186.69,285.75 | 8A.16 186.69,285.75 | R65.2 149.86,285.75 | 90.17,285.75 R62.2 | 1A.14 44.45,285.75 | 3A.5 76.2,271.78 71.12,276.86 71.12,280.67 | 71.12,280.67 71.12,285.75 | 2A.14 71.12,280.67 | 4A.14 105.41,285.75 | 5A.16 125.73,285.75 | 6A.16 146.05,285.75 | 7A.14 166.37,285.75 | 44.45,252.73 71.12,252.73 | 71.12,252.73 105.41,252.73 | 105.41,252.73 125.73,252.73 | 125.73,252.73 146.05,252.73 | 146.05,252.73 166.37,252.73 | 166.37,252.73 186.69,252.73 | 186.69,252.73 207.01,252.73 9B.16 | 8B.16 186.69,252.73 | 7B.14 166.37,252.73 | 6B.16 146.05,252.73 | 5B.16 125.73,252.73 | 4B.14 105.41,252.73 | 3B.5 76.2,236.22 71.12,241.3 71.12,248.92 | 71.12,248.92 71.12,252.73 | 71.12,248.92 2B.20 | 1B.20 44.45,252.73 | 44.45,217.17 C12.1 v35.56,217.17 | 44.45,217.17 C13.1 71.12,217.17 | 71.12,217.17 C14.1 C15.1 105.41,217.17 | 105.41,217.17 C16.1 128.27,217.17 | 128.27,217.17 C17.1 146.05,217.17 | 146.05,217.17 C18.1 166.37,217.17 | 166.37,217.17 C53.1 186.69,217.17 | 186.69,217.17 C54.1 207.01,217.17 | 207.01,217.17 C55.1 227.33,217.17 10C.14 | 9C.16 207.01,217.17 | 186.69,217.17 8C.16 | 7C.14 166.37,217.17 | 6C.14 146.05,217.17 | 5C.16 128.27,210.82 | 128.27,210.82 R64.2 | 128.27,210.82 128.27,217.17 | 4C.14 105.41,217.17 | 3C.5 76.2,200.66 71.12,205.74 71.12,209.55 | 71.12,209.55 71.12,217.17 | 2C.14 71.12,209.55 | 1C.20 44.45,217.17 | 64.77,180.34 44.45,180.34 | 44.45,180.34 v35.56,180.34 | 64.77,180.34 71.12,180.34
  Bottom 1.016: 71.12,180.34 R63.2 105.41,180.34 | 105.41,180.34 125.73,180.34 5D.16 | 4D.14 105.41,180.34 | 3D.5 76.35,166.22 76.22,166.22 71.12,171.32 71.12,180.34 | 2D.20 64.77,180.34 | 5E.16 125.73,142.24 105.41,142.24 | 44.45,142.24 71.12,142.24 | 71.12,142.24 105.41,142.24 | 4E.14 105.41,142.24 | 3E.5 76.2,129.54 71.12,134.62 71.12,138.43 | 71.12,138.43 71.12,142.24 | 2E.14 71.12,138.43 | 1E.14 44.45,142.24 | 105.41,109.22 128.27,109.22 128.27,104.14 | 105.41,109.22 71.12,109.22 | 71.12,109.22 64.77,109.22 | 64.77,109.22 44.45,109.22 | 44.45,109.22 v35.56,109.22 | R66.2 128.27,104.14 | 128.27,104.14 5F.16 | 4F.14 105.41,109.22 | 3F.5 76.35,95.1 76.22,95.1 71.12,100.2 71.12,109.22 | 2F.20 64.77,109.22 | 44.45,74.93 C56.1 v35.56,74.93 | 44.45,74.93 C57.1 64.77,74.93 | 64.77,74.93 C58.1 85.09,74.93 | 85.09,74.93 C59.1 105.41,74.93 | 105.41,74.93 C60.1 125.73,74.93 5G.16 | 4G.14 105.41,74.93 | 3G.14 85.09,74.93 | 2G.14 64.77,74.93 | 1G.20 44.45,74.93 | 109.22,41.91 128.27,41.91 128.27,33.02 | 109.22,41.91 85.09,41.91 | 85.09,41.91 64.77,41.91 | 64.77,41.91 44.45,41.91 | R61.2 128.27,33.02 | 128.27,33.02 5H.16 | 4H.24 109.22,41.91 | 3H.16 85.09,41.91 | 2H.14 64.77,41.91 | H1.14 44.45,41.91 | v35.56,41.91 44.45,41.91 | 44.45,142.24 v35.56,142.24 | v35.56,252.73 44.45,252.73 | 44.45,285.75 v25.4,285.75 | 1D.20 44.45,180.34 | 1F.20 44.45,109.22
  Bottom 2.54: P1.1 5.08,189.94 v5.08,187.96 5.08,186.49 P1.2
VECTORCOMPLETE  (1 unrouted)
VRAM0  (4 unrouted)
VRAM1  (4 unrouted)
VRAM2  (4 unrouted)
VRAM3  (4 unrouted)
VRAM4  (4 unrouted)
VRAM5  (4 unrouted)
VRAM6  (4 unrouted)
VRAM7  (4 unrouted)
VRAM8  (3 unrouted)
VRAM9  (3 unrouted)
VRAM10  (3 unrouted)
VRAM11  (3 unrouted)
VRAMPC  (2 unrouted)
XBRM1  (1 unrouted)
XBRM2  (1 unrouted)
XBRM3  (1 unrouted)
XBRM4  (2 unrouted)
XBRM5  (1 unrouted)
XBRM6  (1 unrouted)
XBRM7  (1 unrouted)
XBRM8  (2 unrouted)
XBRM9  (1 unrouted)
XBRM10  (1 unrouted)
XBRM11  (1 unrouted)
XBRM12  (2 unrouted)
XBRMCLK  (2 unrouted)
XEND1  (4 unrouted)
XEND2  (4 unrouted)
XEND3  (4 unrouted)
XEND4  (4 unrouted)
XEND5  (4 unrouted)
XEND6  (4 unrouted)
XEND7  (4 unrouted)
XEND8  (4 unrouted)
XEND9  (4 unrouted)
XEND10  (4 unrouted)
XEND11  (4 unrouted)
XEND12  (4 unrouted)
XOUT  (4 unrouted)
XRATE  (3 unrouted)
YBRM1  (1 unrouted)
YBRM2  (1 unrouted)
YBRM3  (1 unrouted)
YBRM4  (2 unrouted)
YBRM5  (1 unrouted)
YBRM6  (1 unrouted)
YBRM7  (1 unrouted)
YBRM8  (2 unrouted)
YBRM9  (1 unrouted)
YBRM10  (1 unrouted)
YBRM11  (1 unrouted)
YBRM12  (2 unrouted)
YBRMCLK  (2 unrouted)
YEND1  (4 unrouted)
YEND2  (4 unrouted)
YEND3  (4 unrouted)
YEND4  (4 unrouted)
YEND5  (4 unrouted)
YEND6  (4 unrouted)
YEND7  (4 unrouted)
YEND8  (4 unrouted)
YEND9  (4 unrouted)
YEND10  (4 unrouted)
YEND11  (4 unrouted)
YEND12  (4 unrouted)
YOUT  (4 unrouted)
YRATE  (3 unrouted)
ZOUT  (2 unrouted)

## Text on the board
Top: 1 | 2 | 3 | 4 | 5 | 6 | 7 | 8 | 9 | Note: The analog circuits on this board / were NOT designed by Kincaid Arcade; / they were copied from the Atari Asteroids / Deluxe Manual. This project is intended / ONLY as a hobbyist's attempt to make a / vector arcade game, and neither Alexander / Haley nor Kincaid Arcade claim copyright or / ownership on any of the analog circuits. | A | Kincaid Arcade | Vector Generator | Board | (c) Kincaid Arcade | 2/7/2020 | Digital Circuits | Designed By: | B | Alexander K. Haley | (A 16 Year Old!) | +5V | C | Power Supply | +5V / DAC | +15V | -15V | D | X Analog Circuitry | X Gain | E | X Center | F | Y Analog Circuitry | Y Gain | G | Y Center | H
